VERSION 5.8 ;
BUSBITCHARS "[]" ;
DIVIDERCHAR "/" ;
UNITS
    DATABASE MICRONS 1000 ;
END UNITS

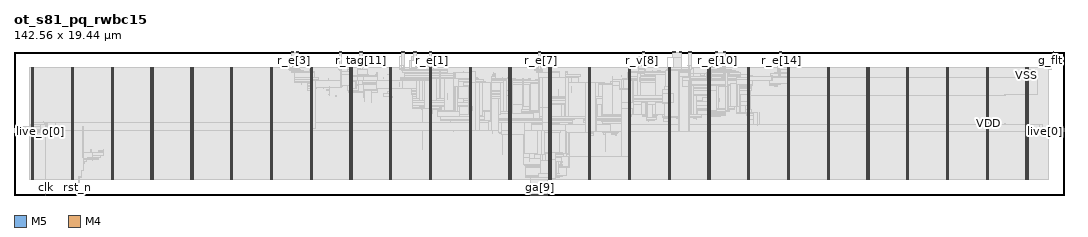
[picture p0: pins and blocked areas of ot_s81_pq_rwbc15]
MACRO ot_s81_pq_rwbc15
  FOREIGN ot_s81_pq_rwbc15 0 0 ;
  CLASS BLOCK ;
  SIZE 142.56 BY 19.44 ;
  PIN clk
    DIRECTION INPUT ;
    USE SIGNAL ;
    PORT
      LAYER M5 ;
        RECT  4.32 0 4.344 0.084 ;
    END
  END clk
  PIN g_flt
    DIRECTION INPUT ;
    USE SIGNAL ;
    PORT
      LAYER M5 ;
        RECT  141.12 19.356 141.144 19.44 ;
    END
  END g_flt
  PIN ga[0]
    DIRECTION OUTPUT ;
    USE SIGNAL ;
    PORT
      LAYER M5 ;
        RECT  70.128 0 70.152 0.084 ;
    END
  END ga[0]
  PIN ga[10]
    DIRECTION OUTPUT ;
    USE SIGNAL ;
    PORT
      LAYER M5 ;
        RECT  71.568 0 71.592 0.084 ;
    END
  END ga[10]
  PIN ga[11]
    DIRECTION OUTPUT ;
    USE SIGNAL ;
    PORT
      LAYER M5 ;
        RECT  71.712 0 71.736 0.084 ;
    END
  END ga[11]
  PIN ga[12]
    DIRECTION OUTPUT ;
    USE SIGNAL ;
    PORT
      LAYER M5 ;
        RECT  71.856 0 71.88 0.084 ;
    END
  END ga[12]
  PIN ga[13]
    DIRECTION OUTPUT ;
    USE SIGNAL ;
    PORT
      LAYER M5 ;
        RECT  72 0 72.024 0.084 ;
    END
  END ga[13]
  PIN ga[14]
    DIRECTION OUTPUT ;
    USE SIGNAL ;
    PORT
      LAYER M5 ;
        RECT  72.144 0 72.168 0.084 ;
    END
  END ga[14]
  PIN ga[15]
    DIRECTION OUTPUT ;
    USE SIGNAL ;
    PORT
      LAYER M5 ;
        RECT  72.288 0 72.312 0.084 ;
    END
  END ga[15]
  PIN ga[1]
    DIRECTION OUTPUT ;
    USE SIGNAL ;
    PORT
      LAYER M5 ;
        RECT  70.272 0 70.296 0.084 ;
    END
  END ga[1]
  PIN ga[2]
    DIRECTION OUTPUT ;
    USE SIGNAL ;
    PORT
      LAYER M5 ;
        RECT  70.416 0 70.44 0.084 ;
    END
  END ga[2]
  PIN ga[3]
    DIRECTION OUTPUT ;
    USE SIGNAL ;
    PORT
      LAYER M5 ;
        RECT  70.56 0 70.584 0.084 ;
    END
  END ga[3]
  PIN ga[4]
    DIRECTION OUTPUT ;
    USE SIGNAL ;
    PORT
      LAYER M5 ;
        RECT  70.704 0 70.728 0.084 ;
    END
  END ga[4]
  PIN ga[5]
    DIRECTION OUTPUT ;
    USE SIGNAL ;
    PORT
      LAYER M5 ;
        RECT  70.848 0 70.872 0.084 ;
    END
  END ga[5]
  PIN ga[6]
    DIRECTION OUTPUT ;
    USE SIGNAL ;
    PORT
      LAYER M5 ;
        RECT  70.992 0 71.016 0.084 ;
    END
  END ga[6]
  PIN ga[7]
    DIRECTION OUTPUT ;
    USE SIGNAL ;
    PORT
      LAYER M5 ;
        RECT  71.136 0 71.16 0.084 ;
    END
  END ga[7]
  PIN ga[8]
    DIRECTION OUTPUT ;
    USE SIGNAL ;
    PORT
      LAYER M5 ;
        RECT  71.28 0 71.304 0.084 ;
    END
  END ga[8]
  PIN ga[9]
    DIRECTION OUTPUT ;
    USE SIGNAL ;
    PORT
      LAYER M5 ;
        RECT  71.424 0 71.448 0.084 ;
    END
  END ga[9]
  PIN live[0]
    DIRECTION INPUT ;
    USE SIGNAL ;
    PORT
      LAYER M4 ;
        RECT  142.476 8.64 142.56 8.664 ;
    END
  END live[0]
  PIN live[1]
    DIRECTION INPUT ;
    USE SIGNAL ;
    PORT
      LAYER M4 ;
        RECT  142.476 8.784 142.56 8.808 ;
    END
  END live[1]
  PIN live[2]
    DIRECTION INPUT ;
    USE SIGNAL ;
    PORT
      LAYER M4 ;
        RECT  142.476 8.928 142.56 8.952 ;
    END
  END live[2]
  PIN live[3]
    DIRECTION INPUT ;
    USE SIGNAL ;
    PORT
      LAYER M4 ;
        RECT  142.476 9.072 142.56 9.096 ;
    END
  END live[3]
  PIN live_o[0]
    DIRECTION OUTPUT ;
    USE SIGNAL ;
    PORT
      LAYER M4 ;
        RECT  0 8.64 0.084 8.664 ;
    END
  END live_o[0]
  PIN live_o[1]
    DIRECTION OUTPUT ;
    USE SIGNAL ;
    PORT
      LAYER M4 ;
        RECT  0 8.784 0.084 8.808 ;
    END
  END live_o[1]
  PIN live_o[2]
    DIRECTION OUTPUT ;
    USE SIGNAL ;
    PORT
      LAYER M4 ;
        RECT  0 8.928 0.084 8.952 ;
    END
  END live_o[2]
  PIN live_o[3]
    DIRECTION OUTPUT ;
    USE SIGNAL ;
    PORT
      LAYER M4 ;
        RECT  0 9.072 0.084 9.096 ;
    END
  END live_o[3]
  PIN q2f
    DIRECTION OUTPUT ;
    USE SIGNAL ;
    PORT
      LAYER M5 ;
        RECT  72.432 0 72.456 0.084 ;
    END
  END q2f
  PIN r_e[0]
    DIRECTION INPUT ;
    USE SIGNAL ;
    PORT
      LAYER M5 ;
        RECT  38.592 19.356 38.616 19.44 ;
    END
  END r_e[0]
  PIN r_e[10]
    DIRECTION INPUT ;
    USE SIGNAL ;
    PORT
      LAYER M5 ;
        RECT  95.472 19.356 95.496 19.44 ;
    END
  END r_e[10]
  PIN r_e[11]
    DIRECTION INPUT ;
    USE SIGNAL ;
    PORT
      LAYER M5 ;
        RECT  90.576 19.356 90.6 19.44 ;
    END
  END r_e[11]
  PIN r_e[12]
    DIRECTION INPUT ;
    USE SIGNAL ;
    PORT
      LAYER M5 ;
        RECT  89.76 19.356 89.784 19.44 ;
    END
  END r_e[12]
  PIN r_e[13]
    DIRECTION INPUT ;
    USE SIGNAL ;
    PORT
      LAYER M5 ;
        RECT  96.576 19.356 96.6 19.44 ;
    END
  END r_e[13]
  PIN r_e[14]
    DIRECTION INPUT ;
    USE SIGNAL ;
    PORT
      LAYER M5 ;
        RECT  104.16 19.356 104.184 19.44 ;
    END
  END r_e[14]
  PIN r_e[1]
    DIRECTION INPUT ;
    USE SIGNAL ;
    PORT
      LAYER M5 ;
        RECT  56.688 19.356 56.712 19.44 ;
    END
  END r_e[1]
  PIN r_e[2]
    DIRECTION INPUT ;
    USE SIGNAL ;
    PORT
      LAYER M5 ;
        RECT  52.944 19.356 52.968 19.44 ;
    END
  END r_e[2]
  PIN r_e[3]
    DIRECTION INPUT ;
    USE SIGNAL ;
    PORT
      LAYER M5 ;
        RECT  37.968 19.356 37.992 19.44 ;
    END
  END r_e[3]
  PIN r_e[4]
    DIRECTION INPUT ;
    USE SIGNAL ;
    PORT
      LAYER M5 ;
        RECT  44.448 19.356 44.472 19.44 ;
    END
  END r_e[4]
  PIN r_e[5]
    DIRECTION INPUT ;
    USE SIGNAL ;
    PORT
      LAYER M5 ;
        RECT  47.232 19.356 47.256 19.44 ;
    END
  END r_e[5]
  PIN r_e[6]
    DIRECTION INPUT ;
    USE SIGNAL ;
    PORT
      LAYER M5 ;
        RECT  54.576 19.356 54.6 19.44 ;
    END
  END r_e[6]
  PIN r_e[7]
    DIRECTION INPUT ;
    USE SIGNAL ;
    PORT
      LAYER M5 ;
        RECT  71.472 19.356 71.496 19.44 ;
    END
  END r_e[7]
  PIN r_e[8]
    DIRECTION INPUT ;
    USE SIGNAL ;
    PORT
      LAYER M5 ;
        RECT  85.584 19.356 85.608 19.44 ;
    END
  END r_e[8]
  PIN r_e[9]
    DIRECTION INPUT ;
    USE SIGNAL ;
    PORT
      LAYER M5 ;
        RECT  91.92 19.356 91.944 19.44 ;
    END
  END r_e[9]
  PIN r_tag[0]
    DIRECTION INPUT ;
    USE SIGNAL ;
    PORT
      LAYER M5 ;
        RECT  38.4 19.356 38.424 19.44 ;
    END
  END r_tag[0]
  PIN r_tag[10]
    DIRECTION INPUT ;
    USE SIGNAL ;
    PORT
      LAYER M5 ;
        RECT  47.04 19.356 47.064 19.44 ;
    END
  END r_tag[10]
  PIN r_tag[11]
    DIRECTION INPUT ;
    USE SIGNAL ;
    PORT
      LAYER M5 ;
        RECT  47.136 19.356 47.16 19.44 ;
    END
  END r_tag[11]
  PIN r_tag[12]
    DIRECTION INPUT ;
    USE SIGNAL ;
    PORT
      LAYER M5 ;
        RECT  54.384 19.356 54.408 19.44 ;
    END
  END r_tag[12]
  PIN r_tag[13]
    DIRECTION INPUT ;
    USE SIGNAL ;
    PORT
      LAYER M5 ;
        RECT  54.48 19.356 54.504 19.44 ;
    END
  END r_tag[13]
  PIN r_tag[14]
    DIRECTION INPUT ;
    USE SIGNAL ;
    PORT
      LAYER M5 ;
        RECT  71.28 19.356 71.304 19.44 ;
    END
  END r_tag[14]
  PIN r_tag[15]
    DIRECTION INPUT ;
    USE SIGNAL ;
    PORT
      LAYER M5 ;
        RECT  71.376 19.356 71.4 19.44 ;
    END
  END r_tag[15]
  PIN r_tag[16]
    DIRECTION INPUT ;
    USE SIGNAL ;
    PORT
      LAYER M5 ;
        RECT  85.392 19.356 85.416 19.44 ;
    END
  END r_tag[16]
  PIN r_tag[17]
    DIRECTION INPUT ;
    USE SIGNAL ;
    PORT
      LAYER M5 ;
        RECT  85.488 19.356 85.512 19.44 ;
    END
  END r_tag[17]
  PIN r_tag[18]
    DIRECTION INPUT ;
    USE SIGNAL ;
    PORT
      LAYER M5 ;
        RECT  91.728 19.356 91.752 19.44 ;
    END
  END r_tag[18]
  PIN r_tag[19]
    DIRECTION INPUT ;
    USE SIGNAL ;
    PORT
      LAYER M5 ;
        RECT  91.824 19.356 91.848 19.44 ;
    END
  END r_tag[19]
  PIN r_tag[1]
    DIRECTION INPUT ;
    USE SIGNAL ;
    PORT
      LAYER M5 ;
        RECT  38.496 19.356 38.52 19.44 ;
    END
  END r_tag[1]
  PIN r_tag[20]
    DIRECTION INPUT ;
    USE SIGNAL ;
    PORT
      LAYER M5 ;
        RECT  95.28 19.356 95.304 19.44 ;
    END
  END r_tag[20]
  PIN r_tag[21]
    DIRECTION INPUT ;
    USE SIGNAL ;
    PORT
      LAYER M5 ;
        RECT  95.376 19.356 95.4 19.44 ;
    END
  END r_tag[21]
  PIN r_tag[22]
    DIRECTION INPUT ;
    USE SIGNAL ;
    PORT
      LAYER M5 ;
        RECT  90.384 19.356 90.408 19.44 ;
    END
  END r_tag[22]
  PIN r_tag[23]
    DIRECTION INPUT ;
    USE SIGNAL ;
    PORT
      LAYER M5 ;
        RECT  90.48 19.356 90.504 19.44 ;
    END
  END r_tag[23]
  PIN r_tag[24]
    DIRECTION INPUT ;
    USE SIGNAL ;
    PORT
      LAYER M5 ;
        RECT  89.568 19.356 89.592 19.44 ;
    END
  END r_tag[24]
  PIN r_tag[25]
    DIRECTION INPUT ;
    USE SIGNAL ;
    PORT
      LAYER M5 ;
        RECT  89.664 19.356 89.688 19.44 ;
    END
  END r_tag[25]
  PIN r_tag[26]
    DIRECTION INPUT ;
    USE SIGNAL ;
    PORT
      LAYER M5 ;
        RECT  96.384 19.356 96.408 19.44 ;
    END
  END r_tag[26]
  PIN r_tag[27]
    DIRECTION INPUT ;
    USE SIGNAL ;
    PORT
      LAYER M5 ;
        RECT  96.48 19.356 96.504 19.44 ;
    END
  END r_tag[27]
  PIN r_tag[28]
    DIRECTION INPUT ;
    USE SIGNAL ;
    PORT
      LAYER M5 ;
        RECT  103.968 19.356 103.992 19.44 ;
    END
  END r_tag[28]
  PIN r_tag[29]
    DIRECTION INPUT ;
    USE SIGNAL ;
    PORT
      LAYER M5 ;
        RECT  104.064 19.356 104.088 19.44 ;
    END
  END r_tag[29]
  PIN r_tag[2]
    DIRECTION INPUT ;
    USE SIGNAL ;
    PORT
      LAYER M5 ;
        RECT  56.496 19.356 56.52 19.44 ;
    END
  END r_tag[2]
  PIN r_tag[3]
    DIRECTION INPUT ;
    USE SIGNAL ;
    PORT
      LAYER M5 ;
        RECT  56.592 19.356 56.616 19.44 ;
    END
  END r_tag[3]
  PIN r_tag[4]
    DIRECTION INPUT ;
    USE SIGNAL ;
    PORT
      LAYER M5 ;
        RECT  52.752 19.356 52.776 19.44 ;
    END
  END r_tag[4]
  PIN r_tag[5]
    DIRECTION INPUT ;
    USE SIGNAL ;
    PORT
      LAYER M5 ;
        RECT  52.848 19.356 52.872 19.44 ;
    END
  END r_tag[5]
  PIN r_tag[6]
    DIRECTION INPUT ;
    USE SIGNAL ;
    PORT
      LAYER M5 ;
        RECT  37.776 19.356 37.8 19.44 ;
    END
  END r_tag[6]
  PIN r_tag[7]
    DIRECTION INPUT ;
    USE SIGNAL ;
    PORT
      LAYER M5 ;
        RECT  37.872 19.356 37.896 19.44 ;
    END
  END r_tag[7]
  PIN r_tag[8]
    DIRECTION INPUT ;
    USE SIGNAL ;
    PORT
      LAYER M5 ;
        RECT  44.256 19.356 44.28 19.44 ;
    END
  END r_tag[8]
  PIN r_tag[9]
    DIRECTION INPUT ;
    USE SIGNAL ;
    PORT
      LAYER M5 ;
        RECT  44.352 19.356 44.376 19.44 ;
    END
  END r_tag[9]
  PIN r_v[0]
    DIRECTION INPUT ;
    USE SIGNAL ;
    PORT
      LAYER M5 ;
        RECT  38.304 19.356 38.328 19.44 ;
    END
  END r_v[0]
  PIN r_v[10]
    DIRECTION INPUT ;
    USE SIGNAL ;
    PORT
      LAYER M5 ;
        RECT  95.184 19.356 95.208 19.44 ;
    END
  END r_v[10]
  PIN r_v[11]
    DIRECTION INPUT ;
    USE SIGNAL ;
    PORT
      LAYER M5 ;
        RECT  90.288 19.356 90.312 19.44 ;
    END
  END r_v[11]
  PIN r_v[12]
    DIRECTION INPUT ;
    USE SIGNAL ;
    PORT
      LAYER M5 ;
        RECT  89.472 19.356 89.496 19.44 ;
    END
  END r_v[12]
  PIN r_v[13]
    DIRECTION INPUT ;
    USE SIGNAL ;
    PORT
      LAYER M5 ;
        RECT  96.288 19.356 96.312 19.44 ;
    END
  END r_v[13]
  PIN r_v[14]
    DIRECTION INPUT ;
    USE SIGNAL ;
    PORT
      LAYER M5 ;
        RECT  103.872 19.356 103.896 19.44 ;
    END
  END r_v[14]
  PIN r_v[1]
    DIRECTION INPUT ;
    USE SIGNAL ;
    PORT
      LAYER M5 ;
        RECT  56.4 19.356 56.424 19.44 ;
    END
  END r_v[1]
  PIN r_v[2]
    DIRECTION INPUT ;
    USE SIGNAL ;
    PORT
      LAYER M5 ;
        RECT  52.656 19.356 52.68 19.44 ;
    END
  END r_v[2]
  PIN r_v[3]
    DIRECTION INPUT ;
    USE SIGNAL ;
    PORT
      LAYER M5 ;
        RECT  37.68 19.356 37.704 19.44 ;
    END
  END r_v[3]
  PIN r_v[4]
    DIRECTION INPUT ;
    USE SIGNAL ;
    PORT
      LAYER M5 ;
        RECT  44.16 19.356 44.184 19.44 ;
    END
  END r_v[4]
  PIN r_v[5]
    DIRECTION INPUT ;
    USE SIGNAL ;
    PORT
      LAYER M5 ;
        RECT  46.944 19.356 46.968 19.44 ;
    END
  END r_v[5]
  PIN r_v[6]
    DIRECTION INPUT ;
    USE SIGNAL ;
    PORT
      LAYER M5 ;
        RECT  54.288 19.356 54.312 19.44 ;
    END
  END r_v[6]
  PIN r_v[7]
    DIRECTION INPUT ;
    USE SIGNAL ;
    PORT
      LAYER M5 ;
        RECT  71.184 19.356 71.208 19.44 ;
    END
  END r_v[7]
  PIN r_v[8]
    DIRECTION INPUT ;
    USE SIGNAL ;
    PORT
      LAYER M5 ;
        RECT  85.296 19.356 85.32 19.44 ;
    END
  END r_v[8]
  PIN r_v[9]
    DIRECTION INPUT ;
    USE SIGNAL ;
    PORT
      LAYER M5 ;
        RECT  91.632 19.356 91.656 19.44 ;
    END
  END r_v[9]
  PIN rst_n
    DIRECTION INPUT ;
    USE SIGNAL ;
    PORT
      LAYER M5 ;
        RECT  8.64 0 8.664 0.084 ;
    END
  END rst_n
  PIN VDD
    DIRECTION INOUT ;
    USE POWER ;
    PORT
      LAYER M5 ;
        RECT  137.592 2.151 137.712 17.289 ;
        RECT  132.192 2.151 132.312 17.289 ;
        RECT  126.792 2.151 126.912 17.289 ;
        RECT  121.392 2.151 121.512 17.289 ;
        RECT  115.992 2.151 116.112 17.289 ;
        RECT  110.592 2.151 110.712 17.289 ;
        RECT  105.192 2.151 105.312 17.289 ;
        RECT  99.792 2.151 99.912 17.289 ;
        RECT  94.392 2.151 94.512 17.289 ;
        RECT  88.992 2.151 89.112 17.289 ;
        RECT  83.592 2.151 83.712 17.289 ;
        RECT  78.192 2.151 78.312 17.289 ;
        RECT  72.792 2.151 72.912 17.289 ;
        RECT  67.392 2.151 67.512 17.289 ;
        RECT  61.992 2.151 62.112 17.289 ;
        RECT  56.592 2.151 56.712 17.289 ;
        RECT  51.192 2.151 51.312 17.289 ;
        RECT  45.792 2.151 45.912 17.289 ;
        RECT  40.392 2.151 40.512 17.289 ;
        RECT  34.992 2.151 35.112 17.289 ;
        RECT  29.592 2.151 29.712 17.289 ;
        RECT  24.192 2.151 24.312 17.289 ;
        RECT  18.792 2.151 18.912 17.289 ;
        RECT  13.392 2.151 13.512 17.289 ;
        RECT  7.992 2.151 8.112 17.289 ;
        RECT  2.592 2.151 2.712 17.289 ;
    END
  END VDD
  PIN VSS
    DIRECTION INOUT ;
    USE GROUND ;
    PORT
      LAYER M5 ;
        RECT  137.4 2.137 137.52 17.303 ;
        RECT  132 2.137 132.12 17.303 ;
        RECT  126.6 2.137 126.72 17.303 ;
        RECT  121.2 2.137 121.32 17.303 ;
        RECT  115.8 2.137 115.92 17.303 ;
        RECT  110.4 2.137 110.52 17.303 ;
        RECT  105 2.137 105.12 17.303 ;
        RECT  99.6 2.137 99.72 17.303 ;
        RECT  94.2 2.137 94.32 17.303 ;
        RECT  88.8 2.137 88.92 17.303 ;
        RECT  83.4 2.137 83.52 17.303 ;
        RECT  78 2.137 78.12 17.303 ;
        RECT  72.6 2.137 72.72 17.303 ;
        RECT  67.2 2.137 67.32 17.303 ;
        RECT  61.8 2.137 61.92 17.303 ;
        RECT  56.4 2.137 56.52 17.303 ;
        RECT  51 2.137 51.12 17.303 ;
        RECT  45.6 2.137 45.72 17.303 ;
        RECT  40.2 2.137 40.32 17.303 ;
        RECT  34.8 2.137 34.92 17.303 ;
        RECT  29.4 2.137 29.52 17.303 ;
        RECT  24 2.137 24.12 17.303 ;
        RECT  18.6 2.137 18.72 17.303 ;
        RECT  13.2 2.137 13.32 17.303 ;
        RECT  7.8 2.137 7.92 17.303 ;
        RECT  2.4 2.137 2.52 17.303 ;
    END
  END VSS
  OBS
    LAYER RVTN ;
     RECT  2.16 2.16 140.4 2.295 ;
     RECT  2.16 2.565 140.4 2.835 ;
     RECT  2.16 3.105 140.4 3.375 ;
     RECT  2.16 3.645 140.4 3.915 ;
     RECT  2.16 4.185 140.4 4.455 ;
     RECT  2.16 4.725 140.4 4.995 ;
     RECT  2.16 5.265 140.4 5.535 ;
     RECT  2.16 5.805 140.4 6.075 ;
     RECT  2.16 6.345 140.4 6.615 ;
     RECT  2.16 6.885 140.4 7.155 ;
     RECT  2.16 7.425 140.4 7.695 ;
     RECT  2.16 7.965 140.4 8.235 ;
     RECT  2.16 8.505 140.4 8.775 ;
     RECT  2.16 9.045 140.4 9.315 ;
     RECT  2.16 9.585 140.4 9.855 ;
     RECT  2.16 10.125 140.4 10.395 ;
     RECT  2.16 10.665 140.4 10.935 ;
     RECT  2.16 11.205 140.4 11.475 ;
     RECT  2.16 11.745 140.4 12.015 ;
     RECT  2.16 12.285 140.4 12.555 ;
     RECT  2.16 12.825 140.4 13.095 ;
     RECT  2.16 13.365 140.4 13.635 ;
     RECT  2.16 13.905 140.4 14.175 ;
     RECT  2.16 14.445 140.4 14.715 ;
     RECT  2.16 14.985 140.4 15.255 ;
     RECT  2.16 15.525 140.4 15.795 ;
     RECT  2.16 16.065 140.4 16.335 ;
     RECT  2.16 16.605 140.4 16.875 ;
     RECT  2.16 17.145 140.4 17.28 ;
    LAYER RVTP ;
     RECT  2.16 2.295 140.4 2.565 ;
     RECT  2.16 2.835 140.4 3.105 ;
     RECT  2.16 3.375 140.4 3.645 ;
     RECT  2.16 3.915 140.4 4.185 ;
     RECT  2.16 4.455 140.4 4.725 ;
     RECT  2.16 4.995 140.4 5.265 ;
     RECT  2.16 5.535 140.4 5.805 ;
     RECT  2.16 6.075 140.4 6.345 ;
     RECT  2.16 6.615 140.4 6.885 ;
     RECT  2.16 7.155 140.4 7.425 ;
     RECT  2.16 7.695 140.4 7.965 ;
     RECT  2.16 8.235 140.4 8.505 ;
     RECT  2.16 8.775 140.4 9.045 ;
     RECT  2.16 9.315 140.4 9.585 ;
     RECT  2.16 9.855 140.4 10.125 ;
     RECT  2.16 10.395 140.4 10.665 ;
     RECT  2.16 10.935 140.4 11.205 ;
     RECT  2.16 11.475 140.4 11.745 ;
     RECT  2.16 12.015 140.4 12.285 ;
     RECT  2.16 12.555 140.4 12.825 ;
     RECT  2.16 13.095 140.4 13.365 ;
     RECT  2.16 13.635 140.4 13.905 ;
     RECT  2.16 14.175 140.4 14.445 ;
     RECT  2.16 14.715 140.4 14.985 ;
     RECT  2.16 15.255 140.4 15.525 ;
     RECT  2.16 15.795 140.4 16.065 ;
     RECT  2.16 16.335 140.4 16.605 ;
     RECT  2.16 16.875 140.4 17.145 ;
    LAYER M1 ;
     RECT  2.16 2.151 140.4 17.289 ;
    LAYER M2 ;
     RECT  0.103 8.514 0.535 8.532 ;
     RECT  0.535 8.316 2.16 8.532 ;
     RECT  2.16 2.151 71.671 17.289 ;
     RECT  71.671 2.106 72.995 17.289 ;
     RECT  72.995 2.151 140.4 17.289 ;
     RECT  140.4 17.082 140.819 17.1 ;
    LAYER M3 ;
     RECT  70.956 0.091 71.658 0.523 ;
     RECT  70.704 0.523 71.658 1.099 ;
     RECT  70.272 1.099 71.658 1.723 ;
     RECT  70.272 1.723 72.198 2.143 ;
     RECT  72.972 2.101 72.99 2.143 ;
     RECT  70.272 2.143 72.99 2.263 ;
     RECT  70.2 2.263 72.99 2.299 ;
     RECT  8.82 1.723 8.838 2.335 ;
     RECT  70.128 2.299 73.458 2.335 ;
     RECT  8.82 2.335 9.018 2.371 ;
     RECT  69.48 2.335 73.458 2.371 ;
     RECT  2.415 2.143 2.505 2.413 ;
     RECT  7.815 2.143 7.905 2.413 ;
     RECT  13.215 2.143 13.305 2.413 ;
     RECT  18.615 2.143 18.705 2.413 ;
     RECT  24.015 2.143 24.105 2.413 ;
     RECT  29.415 2.143 29.505 2.413 ;
     RECT  34.815 2.143 34.905 2.413 ;
     RECT  40.215 2.143 40.305 2.413 ;
     RECT  45.615 2.143 45.705 2.413 ;
     RECT  51.015 2.143 51.105 2.413 ;
     RECT  56.415 2.143 56.505 2.413 ;
     RECT  61.815 2.143 61.905 2.413 ;
     RECT  67.215 2.143 67.305 2.413 ;
     RECT  78.015 2.143 78.105 2.413 ;
     RECT  83.415 2.143 83.505 2.413 ;
     RECT  88.815 2.143 88.905 2.413 ;
     RECT  94.215 2.143 94.305 2.413 ;
     RECT  99.615 2.143 99.705 2.413 ;
     RECT  105.015 2.143 105.105 2.413 ;
     RECT  110.415 2.143 110.505 2.413 ;
     RECT  115.815 2.143 115.905 2.413 ;
     RECT  121.215 2.143 121.305 2.413 ;
     RECT  126.615 2.143 126.705 2.413 ;
     RECT  132.015 2.143 132.105 2.413 ;
     RECT  137.415 2.143 137.505 2.413 ;
     RECT  69.48 2.371 73.998 2.497 ;
     RECT  8.82 2.371 9.126 2.525 ;
     RECT  69.48 2.497 74.466 2.641 ;
     RECT  9.108 2.525 9.126 3.271 ;
     RECT  9.108 3.271 9.45 3.335 ;
     RECT  69.48 2.641 74.97 3.685 ;
     RECT  69.48 3.685 75.402 3.839 ;
     RECT  69.48 3.839 74.502 3.955 ;
     RECT  69.372 3.955 74.502 4.109 ;
     RECT  69.372 4.109 74.394 4.117 ;
     RECT  9.432 3.335 9.45 4.145 ;
     RECT  9.468 4.261 9.594 4.531 ;
     RECT  9.468 4.531 9.81 4.765 ;
     RECT  10.62 4.729 10.638 4.765 ;
     RECT  9.468 4.765 10.746 4.801 ;
     RECT  9.468 4.801 11.43 4.919 ;
     RECT  10.044 4.919 11.43 5.027 ;
     RECT  10.116 5.027 11.43 5.035 ;
     RECT  10.116 5.035 11.574 5.063 ;
     RECT  69.156 4.117 74.394 5.069 ;
     RECT  10.62 5.063 11.574 5.071 ;
     RECT  9.288 5.071 9.306 5.117 ;
     RECT  69.3 5.069 74.394 5.179 ;
     RECT  75.312 3.839 75.402 5.179 ;
     RECT  10.62 5.071 11.79 5.305 ;
     RECT  69.3 5.179 75.402 5.459 ;
     RECT  71.892 5.459 75.402 5.549 ;
     RECT  69.3 5.459 71.046 5.603 ;
     RECT  71.964 5.549 75.402 5.693 ;
     RECT  10.62 5.305 12.186 5.729 ;
     RECT  71.964 5.693 74.394 5.741 ;
     RECT  11.304 5.729 12.186 5.765 ;
     RECT  11.412 5.765 12.186 5.909 ;
     RECT  11.52 5.909 12.186 5.999 ;
     RECT  11.916 5.999 12.186 6.107 ;
     RECT  10.44 5.803 10.458 6.143 ;
     RECT  12.168 6.107 12.186 6.143 ;
     RECT  78.015 2.413 78.297 8.131 ;
     RECT  81.612 8.131 81.738 8.203 ;
     RECT  80.244 5.971 80.262 8.239 ;
     RECT  81.072 8.203 81.738 8.275 ;
     RECT  2.415 2.413 2.697 8.311 ;
     RECT  66.348 5.539 66.366 8.311 ;
     RECT  78.015 8.131 78.678 8.311 ;
     RECT  2.415 8.311 3.15 8.401 ;
     RECT  81.072 8.275 81.846 8.401 ;
     RECT  78.015 8.311 78.714 8.429 ;
     RECT  65.952 8.311 66.366 8.437 ;
     RECT  67.215 2.413 67.497 8.437 ;
     RECT  80.064 8.239 80.262 8.437 ;
     RECT  81.072 8.401 81.882 8.437 ;
     RECT  80.064 8.437 81.882 8.473 ;
     RECT  65.808 8.437 67.497 8.477 ;
     RECT  0.54 8.311 0.558 8.509 ;
     RECT  2.415 8.401 3.222 8.509 ;
     RECT  71.964 5.741 74.106 8.509 ;
     RECT  78.015 8.429 78.678 8.537 ;
     RECT  2.415 8.509 3.258 8.545 ;
     RECT  79.848 8.473 81.99 8.545 ;
     RECT  79.848 8.545 82.062 8.573 ;
     RECT  66.24 8.477 67.497 8.581 ;
     RECT  139.788 8.437 139.806 8.581 ;
     RECT  0.108 8.509 0.558 8.669 ;
     RECT  2.415 8.545 3.654 8.671 ;
     RECT  88.815 2.413 89.097 8.671 ;
     RECT  99.615 2.413 99.897 8.671 ;
     RECT  110.415 2.413 110.697 8.671 ;
     RECT  121.215 2.413 121.497 8.671 ;
     RECT  132.015 2.413 132.297 8.671 ;
     RECT  139.788 8.581 139.986 8.671 ;
     RECT  137.415 2.413 137.697 8.683 ;
     RECT  138.852 8.581 138.87 8.683 ;
     RECT  66.24 8.581 67.518 8.699 ;
     RECT  71.964 8.509 74.214 8.699 ;
     RECT  99.504 8.671 99.897 8.707 ;
     RECT  88.704 8.671 89.097 8.717 ;
     RECT  99.504 8.707 99.99 8.717 ;
     RECT  110.304 8.671 110.697 8.717 ;
     RECT  121.104 8.671 121.497 8.717 ;
     RECT  131.904 8.671 132.297 8.717 ;
     RECT  137.304 8.683 137.697 8.735 ;
     RECT  2.415 8.671 4.41 8.743 ;
     RECT  2.415 8.743 4.626 8.771 ;
     RECT  137.415 8.735 137.697 8.779 ;
     RECT  138.528 8.683 138.87 8.779 ;
     RECT  139.608 8.671 139.986 8.779 ;
     RECT  0.54 8.669 0.558 8.813 ;
     RECT  4.392 8.771 4.626 8.813 ;
     RECT  137.415 8.779 139.986 8.813 ;
     RECT  66.24 8.699 67.497 8.843 ;
     RECT  138.924 8.813 139.986 8.843 ;
     RECT  5.58 8.731 5.598 8.851 ;
     RECT  2.415 8.771 3.654 8.923 ;
     RECT  138.996 8.843 139.986 8.923 ;
     RECT  6.66 8.851 6.678 8.941 ;
     RECT  40.215 2.413 40.497 8.941 ;
     RECT  5.364 8.851 5.598 8.969 ;
     RECT  6.66 8.941 7.074 8.969 ;
     RECT  138.996 8.923 140.058 8.969 ;
     RECT  5.436 8.969 5.598 8.971 ;
     RECT  61.815 2.413 62.097 8.977 ;
     RECT  139.068 8.969 140.058 9.005 ;
     RECT  5.436 8.971 5.886 9.011 ;
     RECT  79.956 8.573 82.062 9.013 ;
     RECT  79.956 9.013 82.134 9.049 ;
     RECT  61.815 8.977 62.766 9.085 ;
     RECT  6.804 8.969 7.074 9.101 ;
     RECT  40.215 8.941 40.878 9.121 ;
     RECT  64.98 8.311 64.998 9.121 ;
     RECT  34.815 2.413 35.097 9.205 ;
     RECT  13.215 2.413 13.497 9.211 ;
     RECT  24.015 2.413 24.297 9.211 ;
     RECT  40.215 9.121 41.058 9.211 ;
     RECT  45.615 2.413 45.897 9.211 ;
     RECT  4.392 8.813 4.554 9.239 ;
     RECT  100.8 9.049 100.818 9.239 ;
     RECT  137.415 8.813 138.078 9.239 ;
     RECT  34.704 9.205 35.097 9.245 ;
     RECT  13.104 9.211 13.497 9.248 ;
     RECT  23.904 9.211 24.297 9.248 ;
     RECT  45.504 9.211 45.897 9.248 ;
     RECT  59.652 8.671 59.67 9.307 ;
     RECT  61.815 9.085 63.198 9.307 ;
     RECT  2.376 8.923 3.654 9.319 ;
     RECT  59.472 9.307 59.67 9.319 ;
     RECT  61.704 9.307 63.198 9.319 ;
     RECT  64.332 9.121 64.998 9.319 ;
     RECT  78.015 8.537 78.297 9.319 ;
     RECT  40.104 9.211 41.058 9.341 ;
     RECT  53.028 9.211 53.046 9.341 ;
     RECT  59.472 9.319 60.246 9.355 ;
     RECT  79.956 9.049 82.206 9.355 ;
     RECT  59.472 9.355 60.354 9.391 ;
     RECT  69.3 5.603 71.01 9.391 ;
     RECT  71.964 8.699 74.106 9.391 ;
     RECT  99.615 8.717 99.99 9.391 ;
     RECT  59.472 9.391 60.93 9.481 ;
     RECT  68.544 9.121 68.562 9.481 ;
     RECT  68.256 9.481 68.562 9.517 ;
     RECT  69.3 9.391 74.106 9.517 ;
     RECT  2.304 9.319 3.654 9.545 ;
     RECT  5.868 9.011 5.886 9.545 ;
     RECT  139.212 9.005 139.626 9.545 ;
     RECT  66.348 8.843 67.497 9.553 ;
     RECT  68.256 9.517 74.106 9.553 ;
     RECT  137.415 9.239 137.97 9.581 ;
     RECT  139.212 9.545 139.23 9.581 ;
     RECT  2.34 9.545 3.654 9.589 ;
     RECT  99.615 9.391 100.35 9.589 ;
     RECT  2.34 9.589 4.302 9.617 ;
     RECT  6.012 9.547 6.03 9.617 ;
     RECT  61.704 9.319 65.466 9.625 ;
     RECT  66.348 9.553 74.106 9.625 ;
     RECT  59.292 9.481 60.93 9.661 ;
     RECT  61.704 9.625 74.106 9.661 ;
     RECT  6.804 9.101 6.822 9.689 ;
     RECT  134.532 8.581 134.55 9.689 ;
     RECT  79.956 9.355 82.566 9.691 ;
     RECT  75.312 5.693 75.402 9.751 ;
     RECT  2.415 9.617 4.302 9.779 ;
     RECT  59.292 9.661 74.106 9.823 ;
     RECT  75.312 9.751 75.762 9.823 ;
     RECT  78.015 9.319 78.678 9.859 ;
     RECT  77.724 9.859 78.678 9.895 ;
     RECT  3.96 9.779 3.978 9.923 ;
     RECT  79.956 9.691 82.674 9.931 ;
     RECT  88.815 8.717 89.097 9.931 ;
     RECT  59.292 9.823 75.762 10.057 ;
     RECT  77.256 9.895 78.678 10.057 ;
     RECT  79.776 9.931 82.674 10.057 ;
     RECT  86.148 9.931 86.166 10.057 ;
     RECT  85.932 10.057 86.166 10.093 ;
     RECT  86.904 10.057 86.922 10.093 ;
     RECT  57.96 10.057 75.762 10.157 ;
     RECT  57.96 10.157 63.882 10.193 ;
     RECT  85.932 10.093 86.922 10.201 ;
     RECT  99.576 9.589 100.35 10.201 ;
     RECT  64.656 10.157 75.762 10.291 ;
     RECT  77.256 10.057 82.674 10.291 ;
     RECT  83.415 2.413 83.697 10.291 ;
     RECT  64.656 10.291 76.086 10.319 ;
     RECT  77.256 10.291 83.697 10.363 ;
     RECT  71.352 10.319 76.086 10.399 ;
     RECT  76.932 10.363 83.697 10.399 ;
     RECT  92.7 10.291 92.718 10.399 ;
     RECT  88.236 9.931 89.097 10.435 ;
     RECT  91.224 10.399 91.242 10.435 ;
     RECT  85.932 10.201 87.246 10.471 ;
     RECT  88.128 10.435 89.097 10.471 ;
     RECT  89.964 10.435 90.27 10.471 ;
     RECT  91.116 10.435 91.242 10.471 ;
     RECT  92.232 10.399 92.718 10.471 ;
     RECT  85.932 10.471 87.282 10.555 ;
     RECT  88.092 10.471 89.097 10.561 ;
     RECT  89.964 10.471 92.718 10.561 ;
     RECT  85.86 10.555 87.282 10.597 ;
     RECT  95.868 10.597 95.886 10.633 ;
     RECT  71.352 10.399 83.697 10.669 ;
     RECT  88.092 10.561 93.33 10.669 ;
     RECT  94.215 2.413 94.497 10.669 ;
     RECT  95.76 10.633 95.886 10.669 ;
     RECT  57.96 10.193 63.846 10.705 ;
     RECT  94.215 10.669 95.886 10.741 ;
     RECT  71.352 10.669 83.898 10.769 ;
     RECT  85.356 10.597 87.282 10.831 ;
     RECT  99.54 10.201 100.35 10.831 ;
     RECT  76.752 10.769 83.898 10.867 ;
     RECT  85.356 10.831 87.318 10.867 ;
     RECT  71.352 10.769 75.726 10.895 ;
     RECT  76.752 10.867 83.97 10.895 ;
     RECT  84.96 10.867 87.318 10.933 ;
     RECT  88.092 10.669 93.366 10.933 ;
     RECT  56.415 2.413 56.697 10.975 ;
     RECT  84.96 10.933 93.366 10.987 ;
     RECT  94.215 10.741 96.534 10.987 ;
     RECT  56.376 10.975 56.697 11.011 ;
     RECT  99.468 10.831 100.35 11.011 ;
     RECT  64.656 10.319 70.542 11.129 ;
     RECT  84.96 10.987 96.534 11.129 ;
     RECT  101.16 9.391 101.178 11.165 ;
     RECT  76.932 10.895 83.97 11.173 ;
     RECT  99.396 11.011 100.35 11.173 ;
     RECT  68.94 11.129 70.542 11.179 ;
     RECT  71.352 10.895 75.69 11.179 ;
     RECT  99.36 11.173 100.35 11.201 ;
     RECT  87.804 11.129 96.534 11.245 ;
     RECT  87.804 11.245 96.57 11.281 ;
     RECT  57.492 10.705 63.846 11.371 ;
     RECT  64.656 11.129 67.734 11.371 ;
     RECT  76.932 11.173 84.15 11.371 ;
     RECT  84.96 11.129 86.814 11.371 ;
     RECT  87.804 11.281 96.966 11.371 ;
     RECT  68.94 11.179 75.69 11.399 ;
     RECT  57.492 11.371 67.734 11.435 ;
     RECT  57.492 11.435 66.006 11.507 ;
     RECT  87.804 11.371 97.146 11.551 ;
     RECT  68.94 11.399 74.106 11.579 ;
     RECT  55.44 6.151 55.458 11.641 ;
     RECT  56.376 11.011 56.754 11.641 ;
     RECT  57.492 11.507 65.97 11.641 ;
     RECT  99.36 11.201 100.098 11.669 ;
     RECT  87.804 11.551 97.758 11.741 ;
     RECT  56.376 11.641 65.97 11.749 ;
     RECT  55.332 11.641 55.458 11.785 ;
     RECT  75.168 11.399 75.69 11.785 ;
     RECT  55.152 11.785 55.458 11.821 ;
     RECT  75.168 11.785 76.122 11.911 ;
     RECT  76.932 11.371 86.814 11.911 ;
     RECT  75.168 11.911 86.814 11.939 ;
     RECT  79.92 11.939 86.814 11.947 ;
     RECT  87.804 11.741 91.314 11.947 ;
     RECT  69.048 11.579 74.106 11.975 ;
     RECT  55.044 11.821 55.458 11.983 ;
     RECT  56.232 11.749 65.97 11.983 ;
     RECT  55.044 11.983 65.97 12.083 ;
     RECT  54.108 11.803 54.126 12.091 ;
     RECT  55.044 12.083 62.097 12.091 ;
     RECT  98.532 11.995 98.55 12.091 ;
     RECT  99.36 11.669 99.954 12.091 ;
     RECT  92.052 11.741 97.758 12.181 ;
     RECT  98.532 12.091 99.954 12.181 ;
     RECT  75.168 11.939 79.11 12.289 ;
     RECT  62.892 12.083 65.97 12.361 ;
     RECT  69.048 11.975 70.542 12.361 ;
     RECT  71.676 11.975 74.106 12.361 ;
     RECT  74.844 12.289 79.11 12.361 ;
     RECT  62.892 12.361 66.15 12.487 ;
     RECT  54.108 12.091 62.097 12.551 ;
     RECT  62.892 12.487 66.222 12.559 ;
     RECT  66.96 11.435 67.734 12.559 ;
     RECT  79.92 11.947 91.314 12.631 ;
     RECT  92.052 12.181 99.954 12.631 ;
     RECT  62.892 12.559 67.734 12.757 ;
     RECT  54.108 12.551 60.21 12.829 ;
     RECT  60.984 12.551 62.097 12.829 ;
     RECT  62.892 12.757 67.914 12.829 ;
     RECT  71.676 12.361 79.11 12.893 ;
     RECT  79.92 12.631 99.954 12.901 ;
     RECT  60.984 12.829 67.914 13.055 ;
     RECT  71.676 12.893 77.022 13.063 ;
     RECT  71.568 13.063 77.022 13.091 ;
     RECT  71.568 13.091 76.842 13.099 ;
     RECT  77.904 12.893 79.11 13.135 ;
     RECT  79.92 12.901 99.99 13.135 ;
     RECT  71.388 13.099 76.842 13.199 ;
     RECT  51.015 2.413 51.297 13.261 ;
     RECT  47.592 12.631 47.61 13.297 ;
     RECT  51.015 13.261 51.354 13.369 ;
     RECT  54.072 12.829 60.21 13.369 ;
     RECT  68.976 12.361 70.542 13.369 ;
     RECT  71.388 13.199 76.77 13.369 ;
     RECT  50.724 13.369 51.354 13.397 ;
     RECT  50.724 13.397 51.297 13.405 ;
     RECT  54.072 13.369 60.246 13.441 ;
     RECT  60.984 13.055 67.698 13.441 ;
     RECT  110.415 8.717 110.697 13.525 ;
     RECT  121.215 8.717 121.497 13.531 ;
     RECT  132.015 8.717 132.297 13.531 ;
     RECT  43.704 13.369 43.722 13.559 ;
     RECT  68.868 13.369 76.77 13.559 ;
     RECT  110.304 13.525 110.697 13.565 ;
     RECT  77.904 13.135 99.99 13.568 ;
     RECT  121.104 13.531 121.497 13.568 ;
     RECT  131.904 13.531 132.297 13.568 ;
     RECT  54.072 13.441 67.698 13.639 ;
     RECT  77.94 13.568 99.99 13.639 ;
     RECT  134.532 13.531 134.55 13.661 ;
     RECT  42.768 13.531 42.786 13.711 ;
     RECT  68.868 13.559 76.626 13.801 ;
     RECT  50.184 13.405 51.297 13.829 ;
     RECT  53.964 13.639 67.698 13.837 ;
     RECT  45.615 9.248 45.897 13.945 ;
     RECT  45.36 13.945 46.53 13.981 ;
     RECT  47.412 13.297 47.61 13.981 ;
     RECT  48.564 12.595 48.582 13.981 ;
     RECT  45.36 13.981 47.61 14.099 ;
     RECT  50.688 13.829 51.297 14.099 ;
     RECT  53.964 13.837 67.806 14.107 ;
     RECT  68.616 13.801 76.626 14.107 ;
     RECT  53.964 14.107 76.626 14.135 ;
     RECT  40.215 9.341 40.497 14.143 ;
     RECT  45.36 14.099 46.71 14.179 ;
     RECT  42.768 13.711 42.894 14.215 ;
     RECT  47.484 14.099 47.61 14.251 ;
     RECT  48.564 13.981 49.41 14.251 ;
     RECT  77.94 13.639 100.026 14.251 ;
     RECT  42.444 14.215 42.894 14.369 ;
     RECT  47.484 14.251 49.41 14.369 ;
     RECT  77.94 14.251 100.098 14.405 ;
     RECT  53.964 14.135 63.234 14.443 ;
     RECT  79.236 14.405 100.098 14.485 ;
     RECT  39.852 14.143 40.497 14.521 ;
     RECT  41.976 14.485 41.994 14.611 ;
     RECT  77.94 14.405 78.354 14.611 ;
     RECT  53.424 14.443 63.234 14.635 ;
     RECT  53.316 14.635 63.234 14.639 ;
     RECT  79.236 14.485 100.17 14.639 ;
     RECT  64.152 14.135 76.626 14.647 ;
     RECT  77.436 14.611 78.354 14.647 ;
     RECT  79.344 14.639 100.17 14.675 ;
     RECT  39.852 14.521 41.022 14.791 ;
     RECT  41.796 14.611 41.994 14.791 ;
     RECT  44.352 14.635 44.37 14.791 ;
     RECT  52.344 14.731 52.362 14.791 ;
     RECT  53.316 14.639 60.318 14.791 ;
     RECT  103.608 14.755 103.626 14.791 ;
     RECT  43.02 14.791 44.55 14.875 ;
     RECT  45.324 14.179 46.71 14.875 ;
     RECT  61.092 14.639 63.234 14.881 ;
     RECT  64.152 14.647 78.354 14.881 ;
     RECT  82.656 14.675 100.17 14.881 ;
     RECT  103.32 14.791 103.626 14.881 ;
     RECT  39.852 14.791 41.994 14.909 ;
     RECT  43.02 14.875 46.71 14.909 ;
     RECT  61.092 14.881 78.354 14.909 ;
     RECT  50.148 14.881 50.166 14.917 ;
     RECT  51.015 14.099 51.297 14.917 ;
     RECT  44.208 14.909 44.226 14.945 ;
     RECT  45.108 14.909 46.71 14.971 ;
     RECT  47.484 14.369 49.266 14.971 ;
     RECT  43.02 14.909 43.29 14.981 ;
     RECT  82.656 14.881 100.206 15.025 ;
     RECT  102.636 14.881 103.626 15.025 ;
     RECT  50.148 14.917 51.297 15.061 ;
     RECT  52.344 14.791 60.318 15.061 ;
     RECT  102.6 15.025 103.626 15.061 ;
     RECT  50.148 15.061 60.318 15.089 ;
     RECT  77.436 14.909 78.297 15.089 ;
     RECT  79.344 14.675 81.918 15.089 ;
     RECT  45.108 14.971 49.266 15.151 ;
     RECT  102.6 15.061 104.13 15.151 ;
     RECT  105.015 2.413 105.297 15.151 ;
     RECT  39.852 14.909 41.886 15.179 ;
     RECT  45.108 15.151 49.41 15.179 ;
     RECT  79.344 15.089 81.63 15.179 ;
     RECT  79.344 15.179 80.226 15.215 ;
     RECT  61.092 14.909 76.698 15.251 ;
     RECT  45.252 15.179 49.41 15.259 ;
     RECT  50.616 15.089 60.318 15.287 ;
     RECT  79.344 15.215 79.542 15.293 ;
     RECT  39.06 15.025 39.078 15.307 ;
     RECT  79.524 15.293 79.542 15.323 ;
     RECT  38.052 15.307 39.078 15.331 ;
     RECT  39.852 15.179 41.598 15.331 ;
     RECT  61.092 15.251 74.934 15.341 ;
     RECT  45.252 15.259 49.626 15.359 ;
     RECT  61.092 15.341 64.026 15.359 ;
     RECT  80.964 15.179 81.27 15.359 ;
     RECT  38.052 15.331 41.598 15.449 ;
     RECT  47.412 15.359 49.626 15.449 ;
     RECT  52.416 15.287 60.318 15.457 ;
     RECT  61.092 15.359 63.774 15.457 ;
     RECT  50.616 15.287 51.297 15.485 ;
     RECT  64.836 15.341 74.934 15.485 ;
     RECT  82.656 15.025 100.278 15.493 ;
     RECT  82.656 15.493 100.314 15.533 ;
     RECT  70.812 15.485 74.142 15.557 ;
     RECT  99.54 15.533 100.314 15.601 ;
     RECT  70.812 15.557 74.106 15.629 ;
     RECT  82.656 15.533 98.802 15.685 ;
     RECT  38.052 15.449 41.346 15.719 ;
     RECT  52.416 15.457 63.774 15.719 ;
     RECT  64.836 15.485 70.074 15.719 ;
     RECT  71.1 15.629 74.106 15.719 ;
     RECT  42.732 15.601 42.75 15.791 ;
     RECT  64.836 15.719 68.022 15.791 ;
     RECT  69.084 15.719 69.102 15.791 ;
     RECT  71.208 15.719 74.106 15.791 ;
     RECT  52.488 15.719 63.054 15.827 ;
     RECT  69.912 15.719 70.074 15.827 ;
     RECT  82.62 15.685 98.802 15.827 ;
     RECT  99.54 15.601 100.674 15.827 ;
     RECT  52.488 15.827 62.982 15.863 ;
     RECT  66.276 15.791 68.022 15.863 ;
     RECT  69.912 15.827 69.93 15.863 ;
     RECT  52.488 15.863 62.874 15.899 ;
     RECT  67.032 15.863 67.554 15.899 ;
     RECT  74.916 15.485 74.934 15.979 ;
     RECT  75.672 15.251 76.698 15.979 ;
     RECT  137.415 9.581 137.697 15.979 ;
     RECT  38.052 15.719 41.31 15.989 ;
     RECT  50.148 15.835 50.166 15.989 ;
     RECT  52.956 15.899 62.874 15.989 ;
     RECT  66.276 15.863 66.294 15.989 ;
     RECT  67.14 15.899 67.554 15.989 ;
     RECT  64.836 15.791 65.358 16.025 ;
     RECT  81.252 15.359 81.27 16.025 ;
     RECT  83.304 15.827 98.802 16.025 ;
     RECT  102.6 15.151 105.297 16.109 ;
     RECT  99.54 15.827 100.386 16.133 ;
     RECT  44.316 16.105 44.334 16.141 ;
     RECT  45.252 15.359 46.674 16.141 ;
     RECT  47.412 15.449 49.41 16.141 ;
     RECT  74.916 15.979 76.698 16.141 ;
     RECT  137.415 15.979 137.754 16.141 ;
     RECT  138.996 13.627 139.014 16.141 ;
     RECT  102.636 16.109 105.297 16.142 ;
     RECT  99.54 16.133 100.314 16.169 ;
     RECT  45.252 16.141 49.41 16.259 ;
     RECT  52.956 15.989 62.694 16.259 ;
     RECT  64.944 16.025 65.358 16.259 ;
     RECT  82.476 16.105 82.494 16.259 ;
     RECT  93.204 16.025 98.802 16.259 ;
     RECT  99.54 16.169 99.99 16.259 ;
     RECT  137.415 16.141 139.014 16.259 ;
     RECT  46.62 16.259 48.186 16.295 ;
     RECT  49.14 16.259 49.41 16.295 ;
     RECT  64.944 16.259 65.322 16.295 ;
     RECT  74.916 16.141 76.878 16.295 ;
     RECT  51.015 15.485 51.297 16.303 ;
     RECT  44.316 16.141 44.478 16.375 ;
     RECT  45.252 16.259 45.897 16.375 ;
     RECT  50.688 16.303 51.297 16.403 ;
     RECT  94.032 16.259 98.658 16.403 ;
     RECT  99.54 16.259 99.897 16.403 ;
     RECT  74.916 16.295 75.15 16.411 ;
     RECT  65.088 16.295 65.322 16.439 ;
     RECT  102.672 16.142 105.297 16.439 ;
     RECT  49.284 16.295 49.41 16.529 ;
     RECT  52.956 16.259 62.622 16.529 ;
     RECT  65.088 16.439 65.214 16.529 ;
     RECT  93.204 16.259 93.258 16.529 ;
     RECT  137.415 16.259 138.726 16.529 ;
     RECT  93.24 16.529 93.258 16.541 ;
     RECT  49.284 16.529 49.302 16.565 ;
     RECT  60.228 16.529 62.622 16.565 ;
     RECT  65.088 16.529 65.106 16.565 ;
     RECT  71.208 15.791 74.034 16.565 ;
     RECT  74.88 16.411 75.15 16.565 ;
     RECT  83.304 16.025 92.286 16.565 ;
     RECT  94.068 16.403 98.622 16.565 ;
     RECT  103.212 16.439 105.297 16.565 ;
     RECT  60.444 16.565 62.622 16.601 ;
     RECT  60.444 16.601 61.074 16.673 ;
     RECT  94.215 16.565 98.622 16.673 ;
     RECT  38.052 15.989 40.806 16.681 ;
     RECT  52.956 16.529 58.878 16.681 ;
     RECT  71.208 16.565 71.766 16.681 ;
     RECT  37.656 16.681 40.806 16.709 ;
     RECT  83.415 16.565 92.286 16.709 ;
     RECT  37.656 16.709 40.497 16.799 ;
     RECT  44.316 16.375 45.897 16.799 ;
     RECT  61.056 16.673 61.074 16.799 ;
     RECT  61.815 16.601 62.622 16.799 ;
     RECT  70.92 16.681 71.766 16.799 ;
     RECT  72.615 16.565 74.034 16.799 ;
     RECT  74.916 16.565 75.15 16.799 ;
     RECT  84.816 16.709 92.286 16.799 ;
     RECT  94.215 16.673 98.406 16.799 ;
     RECT  73.656 16.799 73.674 16.835 ;
     RECT  74.916 16.799 74.934 16.835 ;
     RECT  88.488 16.799 92.286 16.835 ;
     RECT  37.656 16.799 39.294 16.907 ;
     RECT  87.408 16.799 87.75 16.907 ;
     RECT  37.656 16.907 38.862 16.915 ;
     RECT  52.812 16.681 58.878 16.915 ;
     RECT  70.92 16.799 71.694 16.915 ;
     RECT  88.524 16.835 92.286 16.915 ;
     RECT  86.652 16.799 86.67 16.943 ;
     RECT  87.732 16.907 87.75 16.943 ;
     RECT  94.215 16.799 97.938 16.943 ;
     RECT  44.316 16.799 44.478 16.951 ;
     RECT  137.415 16.529 137.97 16.979 ;
     RECT  2.415 9.779 2.697 17.027 ;
     RECT  7.815 2.413 8.097 17.027 ;
     RECT  13.215 9.248 13.497 17.027 ;
     RECT  18.615 2.413 18.897 17.027 ;
     RECT  24.015 9.248 24.297 17.027 ;
     RECT  29.415 2.413 29.697 17.027 ;
     RECT  34.815 9.245 35.097 17.027 ;
     RECT  40.14 16.799 40.497 17.027 ;
     RECT  45.324 16.799 45.897 17.027 ;
     RECT  51.015 16.403 51.297 17.027 ;
     RECT  61.815 16.799 62.097 17.027 ;
     RECT  67.215 15.989 67.497 17.027 ;
     RECT  72.615 16.799 72.897 17.027 ;
     RECT  78.015 15.089 78.297 17.027 ;
     RECT  83.415 16.709 83.697 17.027 ;
     RECT  99.615 16.403 99.897 17.027 ;
     RECT  103.644 16.565 105.297 17.027 ;
     RECT  110.415 13.565 110.697 17.027 ;
     RECT  115.815 2.413 116.097 17.027 ;
     RECT  121.215 13.568 121.497 17.027 ;
     RECT  126.615 2.413 126.897 17.027 ;
     RECT  132.015 13.568 132.297 17.027 ;
     RECT  137.415 16.979 137.697 17.027 ;
     RECT  37.44 16.915 38.862 17.069 ;
     RECT  40.14 17.027 40.305 17.069 ;
     RECT  45.324 17.027 45.705 17.069 ;
     RECT  46.62 16.295 48.042 17.069 ;
     RECT  52.632 16.915 58.878 17.069 ;
     RECT  70.704 16.915 71.694 17.069 ;
     RECT  84.816 16.799 85.806 17.069 ;
     RECT  88.524 16.915 92.322 17.069 ;
     RECT  94.215 16.943 97.47 17.069 ;
     RECT  103.644 17.027 105.105 17.069 ;
     RECT  138.708 16.529 138.726 17.069 ;
     RECT  37.44 17.069 38.79 17.077 ;
     RECT  44.244 16.951 44.478 17.077 ;
     RECT  52.632 17.069 53.01 17.077 ;
     RECT  57.924 17.069 57.942 17.105 ;
     RECT  88.524 17.069 90.63 17.105 ;
     RECT  97.344 17.069 97.362 17.105 ;
     RECT  37.224 17.077 38.79 17.117 ;
     RECT  44.028 17.077 44.478 17.117 ;
     RECT  46.62 17.069 47.286 17.117 ;
     RECT  52.308 17.077 53.01 17.117 ;
     RECT  53.748 17.069 54.63 17.117 ;
     RECT  70.704 17.069 71.55 17.117 ;
     RECT  84.816 17.069 85.626 17.117 ;
     RECT  88.776 17.105 90.63 17.117 ;
     RECT  94.215 17.069 96.498 17.117 ;
     RECT  103.644 17.069 104.202 17.117 ;
     RECT  37.224 17.117 38.754 17.165 ;
     RECT  46.62 17.117 47.178 17.165 ;
     RECT  52.308 17.117 52.902 17.165 ;
     RECT  53.748 17.117 54.522 17.165 ;
     RECT  70.812 17.117 71.442 17.165 ;
     RECT  91.512 17.069 92.214 17.165 ;
     RECT  94.215 17.117 95.418 17.165 ;
     RECT  38.268 17.165 38.754 17.213 ;
     RECT  44.388 17.117 44.442 17.213 ;
     RECT  2.415 17.027 2.505 17.297 ;
     RECT  7.815 17.027 7.905 17.297 ;
     RECT  13.215 17.027 13.305 17.297 ;
     RECT  18.615 17.027 18.705 17.297 ;
     RECT  24.015 17.027 24.105 17.297 ;
     RECT  29.415 17.027 29.505 17.297 ;
     RECT  34.815 17.027 34.905 17.297 ;
     RECT  40.215 17.069 40.305 17.297 ;
     RECT  45.615 17.069 45.705 17.297 ;
     RECT  51.015 17.027 51.105 17.297 ;
     RECT  61.815 17.027 61.905 17.297 ;
     RECT  67.215 17.027 67.305 17.297 ;
     RECT  72.615 17.027 72.705 17.297 ;
     RECT  78.015 17.027 78.105 17.297 ;
     RECT  83.415 17.027 83.505 17.297 ;
     RECT  88.776 17.117 88.905 17.297 ;
     RECT  94.215 17.165 94.806 17.297 ;
     RECT  99.615 17.027 99.705 17.297 ;
     RECT  105.015 17.069 105.105 17.297 ;
     RECT  110.415 17.027 110.505 17.297 ;
     RECT  115.815 17.027 115.905 17.297 ;
     RECT  121.215 17.027 121.305 17.297 ;
     RECT  126.615 17.027 126.705 17.297 ;
     RECT  132.015 17.027 132.105 17.297 ;
     RECT  137.415 17.027 137.505 17.297 ;
     RECT  44.388 17.213 44.406 17.309 ;
     RECT  56.016 17.069 56.898 17.405 ;
     RECT  38.268 17.213 38.286 17.645 ;
     RECT  52.308 17.165 52.65 17.645 ;
     RECT  91.512 17.165 91.53 17.645 ;
     RECT  96.156 17.117 96.498 17.645 ;
     RECT  103.644 17.117 103.95 17.645 ;
     RECT  37.224 17.165 37.458 18.269 ;
     RECT  46.62 17.165 46.638 18.269 ;
     RECT  53.748 17.165 53.946 18.269 ;
     RECT  56.016 17.405 56.214 18.269 ;
     RECT  70.812 17.165 70.83 18.269 ;
     RECT  89.64 17.117 90.054 18.269 ;
     RECT  94.644 17.297 94.806 18.269 ;
     RECT  96.192 17.645 96.21 18.269 ;
     RECT  103.644 17.645 103.662 18.269 ;
     RECT  37.224 18.269 37.242 18.317 ;
     RECT  88.776 17.297 88.794 18.653 ;
     RECT  52.308 17.645 52.326 18.797 ;
     RECT  53.928 18.269 53.946 18.797 ;
     RECT  56.196 18.269 56.214 18.797 ;
     RECT  84.816 17.117 85.518 18.797 ;
     RECT  94.644 18.269 94.662 18.797 ;
     RECT  89.64 18.269 89.658 18.845 ;
     RECT  140.796 17.077 140.814 18.845 ;
     RECT  85.5 18.797 85.518 19.325 ;
    LAYER M4 ;
     RECT  0.06 8.64 0.137 9.096 ;
     RECT  0.137 8.784 0.517 9.096 ;
     RECT  0.517 8.784 0.569 9.288 ;
     RECT  0.569 8.928 2.408 9.288 ;
     RECT  2.408 2.148 2.512 17.292 ;
     RECT  2.512 2.418 2.704 17.022 ;
     RECT  4.165 9.648 4.309 9.672 ;
     RECT  4.309 9.648 4.453 9.864 ;
     RECT  4.453 8.976 4.597 9.864 ;
     RECT  4.597 8.784 5.569 9.864 ;
     RECT  5.569 8.736 7.808 9.864 ;
     RECT  7.808 2.148 7.912 17.292 ;
     RECT  7.912 2.148 8.104 17.022 ;
     RECT  8.629 1.728 8.849 1.752 ;
     RECT  9.277 5.088 9.349 5.112 ;
     RECT  9.349 5.088 9.395 5.832 ;
     RECT  9.395 5.808 10.469 5.832 ;
     RECT  8.104 8.736 13.208 9.864 ;
     RECT  13.208 2.148 13.312 17.292 ;
     RECT  13.312 2.418 13.504 17.022 ;
     RECT  13.504 8.736 18.608 9.864 ;
     RECT  18.608 2.148 18.712 17.292 ;
     RECT  18.712 2.418 18.904 17.022 ;
     RECT  18.904 8.736 24.008 9.864 ;
     RECT  24.008 2.148 24.112 17.292 ;
     RECT  24.112 2.418 24.304 17.022 ;
     RECT  24.304 8.736 29.408 9.864 ;
     RECT  29.408 2.148 29.512 17.292 ;
     RECT  29.512 2.418 29.704 17.022 ;
     RECT  29.704 8.736 34.808 9.864 ;
     RECT  34.808 2.148 34.912 17.292 ;
     RECT  34.912 2.418 35.104 17.022 ;
     RECT  37.213 18.288 37.429 18.312 ;
     RECT  37.429 18.24 37.715 18.312 ;
     RECT  37.753 17.088 37.765 17.112 ;
     RECT  37.715 18.24 37.907 18.264 ;
     RECT  37.765 17.088 38.257 17.16 ;
     RECT  38.257 17.088 38.341 17.64 ;
     RECT  38.041 15.312 38.761 15.336 ;
     RECT  38.341 17.088 38.765 17.208 ;
     RECT  38.761 15.312 38.801 15.432 ;
     RECT  38.765 17.088 38.801 17.112 ;
     RECT  35.104 8.736 40.208 9.864 ;
     RECT  38.801 15.408 40.208 15.432 ;
     RECT  40.208 2.148 40.312 17.292 ;
     RECT  40.312 2.418 40.504 17.022 ;
     RECT  42.757 13.632 42.841 13.656 ;
     RECT  44.017 17.088 44.149 17.112 ;
     RECT  40.504 14.64 44.305 15.48 ;
     RECT  44.149 17.088 44.305 17.304 ;
     RECT  44.305 14.64 44.417 17.304 ;
     RECT  44.417 14.64 44.445 17.208 ;
     RECT  44.445 14.88 44.453 17.208 ;
     RECT  44.453 14.88 44.524 17.112 ;
     RECT  40.504 8.736 45.608 9.864 ;
     RECT  44.524 14.88 45.608 16.296 ;
     RECT  45.608 2.148 45.712 17.292 ;
     RECT  45.712 2.418 45.904 17.022 ;
     RECT  45.904 14.496 46.541 15.48 ;
     RECT  46.541 14.976 46.829 15.48 ;
     RECT  46.609 18.24 46.979 18.264 ;
     RECT  46.933 17.088 47.125 17.112 ;
     RECT  47.125 17.088 47.222 17.16 ;
     RECT  47.222 17.088 47.308 17.112 ;
     RECT  46.829 15.024 47.333 15.48 ;
     RECT  47.333 15.264 49.237 15.48 ;
     RECT  45.904 8.736 51.008 9.864 ;
     RECT  49.237 14.448 51.008 15.48 ;
     RECT  51.008 2.148 51.112 17.292 ;
     RECT  51.112 2.418 51.304 17.022 ;
     RECT  51.304 14.448 52.693 15.48 ;
     RECT  52.621 17.616 52.705 17.64 ;
     RECT  52.297 18.768 52.787 18.792 ;
     RECT  52.837 17.136 52.933 17.16 ;
     RECT  52.933 17.088 52.934 17.16 ;
     RECT  52.934 17.088 53.021 17.112 ;
     RECT  53.737 18.24 53.917 18.264 ;
     RECT  53.917 18.24 54.323 18.792 ;
     RECT  54.323 18.768 54.419 18.792 ;
     RECT  54.469 17.136 54.565 17.16 ;
     RECT  54.565 17.088 54.566 17.16 ;
     RECT  54.061 13.056 54.637 13.08 ;
     RECT  52.693 14.448 54.637 15.528 ;
     RECT  54.566 17.088 54.652 17.112 ;
     RECT  54.637 13.056 55.033 15.528 ;
     RECT  55.033 12.864 55.433 15.528 ;
     RECT  54.097 11.808 55.681 11.832 ;
     RECT  55.433 12.864 55.681 15.48 ;
     RECT  56.005 18.24 56.077 18.264 ;
     RECT  56.077 17.616 56.185 18.264 ;
     RECT  51.304 8.736 56.408 9.864 ;
     RECT  55.681 11.808 56.408 15.48 ;
     RECT  56.185 17.616 56.408 18.792 ;
     RECT  56.408 2.148 56.512 18.792 ;
     RECT  56.512 2.418 56.531 18.792 ;
     RECT  56.531 18.768 56.627 18.792 ;
     RECT  56.531 2.418 56.704 17.4 ;
     RECT  56.704 17.376 56.909 17.4 ;
     RECT  56.704 12.768 57.377 15.816 ;
     RECT  57.377 13.056 57.74 15.816 ;
     RECT  56.704 11.664 57.805 11.688 ;
     RECT  57.74 13.056 57.953 16.776 ;
     RECT  57.805 11.664 57.973 11.976 ;
     RECT  57.973 11.328 58.06 11.976 ;
     RECT  58.06 11.472 58.489 11.976 ;
     RECT  57.953 13.056 58.489 15.816 ;
     RECT  58.489 11.472 59.701 15.816 ;
     RECT  59.701 11.472 59.797 16.584 ;
     RECT  59.797 11.376 60.005 16.584 ;
     RECT  60.005 11.376 60.257 14.808 ;
     RECT  60.257 13.104 60.323 14.808 ;
     RECT  60.257 11.376 60.433 11.976 ;
     RECT  60.433 10.848 60.545 11.976 ;
     RECT  60.545 10.944 61.765 11.976 ;
     RECT  60.323 13.104 61.765 14.76 ;
     RECT  56.704 8.736 61.808 9.864 ;
     RECT  61.765 10.944 61.808 14.76 ;
     RECT  60.005 15.792 61.808 16.584 ;
     RECT  61.808 2.148 61.912 17.292 ;
     RECT  61.912 2.418 62.104 17.022 ;
     RECT  62.104 8.736 62.675 16.776 ;
     RECT  62.675 8.736 63.173 15.336 ;
     RECT  63.173 10.848 63.569 15.336 ;
     RECT  63.173 8.736 64.429 9.864 ;
     RECT  63.569 11.424 64.753 15.336 ;
     RECT  64.429 8.736 64.825 10.008 ;
     RECT  64.753 10.992 64.825 15.336 ;
     RECT  64.825 8.736 64.829 15.336 ;
     RECT  64.829 8.736 65.729 13.128 ;
     RECT  65.729 8.736 65.797 10.008 ;
     RECT  65.797 8.448 65.837 10.008 ;
     RECT  65.729 10.992 66.017 13.128 ;
     RECT  66.017 11.376 66.085 13.128 ;
     RECT  64.829 14.208 66.085 15.336 ;
     RECT  65.837 8.448 66.229 9.864 ;
     RECT  66.085 11.376 66.445 15.336 ;
     RECT  66.445 11.376 66.805 15.576 ;
     RECT  66.229 8.208 67.208 9.864 ;
     RECT  66.805 11.376 67.208 15.816 ;
     RECT  67.208 2.148 67.312 17.292 ;
     RECT  67.312 2.418 67.504 17.022 ;
     RECT  67.504 12.288 67.601 15.816 ;
     RECT  67.601 12.288 67.673 15.576 ;
     RECT  67.673 12.288 69.037 14.952 ;
     RECT  69.037 11.952 69.061 14.952 ;
     RECT  69.061 11.952 69.148 15.768 ;
     RECT  69.144 5.04 69.205 5.064 ;
     RECT  67.504 8.208 69.251 9.864 ;
     RECT  69.205 5.04 69.932 5.592 ;
     RECT  69.148 11.952 70.009 14.952 ;
     RECT  69.932 4.512 70.019 5.592 ;
     RECT  70.009 11.424 70.153 14.952 ;
     RECT  69.251 8.736 70.229 9.864 ;
     RECT  70.22 1.104 70.307 1.128 ;
     RECT  70.117 2.304 70.549 2.328 ;
     RECT  70.019 4.896 70.697 5.592 ;
     RECT  70.693 0.528 70.777 0.552 ;
     RECT  70.837 0.096 71.057 0.168 ;
     RECT  70.153 11.424 71.197 15.096 ;
     RECT  70.549 1.728 71.221 2.328 ;
     RECT  71.197 11.424 71.233 16.008 ;
     RECT  70.801 18.24 71.315 18.264 ;
     RECT  70.693 17.088 71.365 17.112 ;
     RECT  71.233 11.184 71.377 16.008 ;
     RECT  71.221 1.728 71.413 2.952 ;
     RECT  70.697 4.896 71.461 5.544 ;
     RECT  71.365 17.088 71.462 17.16 ;
     RECT  71.462 17.088 71.561 17.112 ;
     RECT  71.413 1.152 71.633 2.952 ;
     RECT  71.057 0.096 71.669 0.12 ;
     RECT  70.229 8.736 71.693 9.576 ;
     RECT  71.377 10.704 71.693 16.008 ;
     RECT  71.461 4.656 71.701 5.544 ;
     RECT  71.701 3.984 72.205 5.544 ;
     RECT  71.633 1.728 72.209 2.952 ;
     RECT  72.209 2.148 72.608 2.952 ;
     RECT  72.205 3.984 72.608 5.592 ;
     RECT  71.693 8.736 72.608 16.008 ;
     RECT  72.608 2.148 72.712 17.292 ;
     RECT  72.712 2.304 72.904 17.022 ;
     RECT  72.904 2.304 73.469 5.736 ;
     RECT  73.469 2.832 73.564 5.736 ;
     RECT  73.564 2.832 73.577 4.68 ;
     RECT  73.577 2.832 73.721 4.488 ;
     RECT  73.721 2.928 73.937 4.488 ;
     RECT  73.937 2.928 74.081 2.952 ;
     RECT  73.937 4.128 74.189 4.488 ;
     RECT  72.904 10.704 74.329 12.312 ;
     RECT  74.189 4.464 74.405 4.488 ;
     RECT  73.564 5.664 74.405 5.736 ;
     RECT  74.405 5.664 74.581 5.688 ;
     RECT  74.329 10.656 74.801 12.312 ;
     RECT  74.801 10.704 74.905 12.312 ;
     RECT  72.904 13.392 74.905 16.008 ;
     RECT  72.904 8.736 74.917 9.576 ;
     RECT  74.581 5.184 74.981 5.688 ;
     RECT  74.905 10.704 75.269 16.008 ;
     RECT  74.917 8.544 77.605 9.576 ;
     RECT  75.269 10.704 77.605 15.288 ;
     RECT  74.981 5.184 78.008 5.208 ;
     RECT  77.605 8.544 78.008 15.288 ;
     RECT  78.008 2.148 78.112 17.292 ;
     RECT  78.112 2.418 78.304 17.022 ;
     RECT  78.304 8.688 78.905 15.288 ;
     RECT  78.905 8.688 79.049 12.312 ;
     RECT  79.049 10.56 79.121 12.312 ;
     RECT  79.121 10.608 79.265 12.312 ;
     RECT  78.905 13.44 79.373 15.288 ;
     RECT  79.265 10.704 79.805 12.312 ;
     RECT  79.805 10.992 79.873 12.312 ;
     RECT  79.373 13.44 79.873 14.952 ;
     RECT  79.049 8.688 80.989 9.576 ;
     RECT  79.873 10.992 81.241 14.952 ;
     RECT  81.212 15.984 81.241 16.008 ;
     RECT  81.241 10.992 81.299 16.008 ;
     RECT  81.299 10.992 82.465 15.72 ;
     RECT  80.989 8.688 82.753 9.72 ;
     RECT  82.465 10.896 82.753 15.72 ;
     RECT  78.304 5.184 83.408 5.208 ;
     RECT  82.753 8.688 83.408 15.72 ;
     RECT  83.408 2.148 83.512 17.292 ;
     RECT  83.512 2.418 83.704 17.022 ;
     RECT  83.704 10.896 83.981 15.48 ;
     RECT  83.981 10.992 84.131 15.48 ;
     RECT  84.131 13.536 84.697 15.48 ;
     RECT  84.697 13.536 85.036 16.44 ;
     RECT  84.131 10.992 85.165 12.312 ;
     RECT  84.805 18.768 85.331 18.792 ;
     RECT  85.237 17.616 85.427 17.64 ;
     RECT  85.445 19.296 85.529 19.32 ;
     RECT  85.036 16.272 85.573 16.44 ;
     RECT  85.573 16.272 85.66 17.112 ;
     RECT  85.165 10.992 85.777 12.552 ;
     RECT  85.777 10.656 85.849 12.552 ;
     RECT  85.849 10.56 85.955 12.552 ;
     RECT  85.955 10.56 86.645 12.312 ;
     RECT  86.645 10.656 86.717 12.312 ;
     RECT  85.036 13.536 87.037 15.24 ;
     RECT  85.66 16.272 87.037 16.296 ;
     RECT  86.717 10.944 87.073 12.312 ;
     RECT  87.073 10.944 88.261 12.552 ;
     RECT  88.261 10.848 88.333 12.552 ;
     RECT  87.037 13.536 88.513 16.296 ;
     RECT  83.704 8.688 88.808 9.576 ;
     RECT  88.333 10.704 88.808 12.552 ;
     RECT  88.513 13.536 88.808 16.92 ;
     RECT  88.808 2.148 88.912 17.292 ;
     RECT  88.912 2.418 89.104 17.112 ;
     RECT  88.765 18.624 89.612 18.648 ;
     RECT  89.612 18.624 89.699 18.84 ;
     RECT  89.104 8.688 90.241 9.576 ;
     RECT  89.104 10.704 90.241 17.112 ;
     RECT  90.241 8.688 90.323 17.112 ;
     RECT  90.025 18.24 90.515 18.264 ;
     RECT  90.323 17.088 90.641 17.112 ;
     RECT  90.323 8.688 91.525 16.104 ;
     RECT  91.501 17.616 91.667 17.64 ;
     RECT  91.525 8.688 91.763 16.584 ;
     RECT  91.763 10.992 91.813 16.584 ;
     RECT  91.813 10.992 91.829 17.16 ;
     RECT  91.829 10.992 92.045 15.528 ;
     RECT  92.045 10.992 92.189 14.808 ;
     RECT  91.829 16.512 92.225 17.16 ;
     RECT  92.189 10.992 92.621 13.56 ;
     RECT  92.621 10.992 92.837 11.736 ;
     RECT  92.225 16.512 93.229 16.536 ;
     RECT  93.229 16.272 93.805 16.536 ;
     RECT  93.805 16.08 94.057 16.536 ;
     RECT  91.763 8.688 94.208 9.576 ;
     RECT  92.837 10.992 94.208 11.496 ;
     RECT  92.621 12.768 94.208 13.56 ;
     RECT  92.189 14.64 94.208 14.808 ;
     RECT  94.057 15.792 94.208 16.536 ;
     RECT  94.208 2.148 94.312 17.292 ;
     RECT  94.312 2.418 94.504 17.022 ;
     RECT  94.504 15.792 94.673 17.022 ;
     RECT  94.633 18.768 94.777 18.792 ;
     RECT  94.777 18.24 95.219 18.792 ;
     RECT  94.504 11.472 95.357 14.808 ;
     RECT  95.357 11.712 95.681 14.808 ;
     RECT  94.673 15.792 96.041 16.104 ;
     RECT  95.365 17.088 96.145 17.16 ;
     RECT  95.219 18.24 96.145 18.264 ;
     RECT  96.041 15.984 96.361 16.104 ;
     RECT  96.145 17.088 96.361 18.264 ;
     RECT  96.361 15.984 96.401 18.264 ;
     RECT  96.401 16.56 96.419 18.264 ;
     RECT  95.681 11.712 96.541 14.76 ;
     RECT  96.419 16.56 96.611 17.64 ;
     RECT  96.541 11.472 96.853 14.76 ;
     RECT  96.611 16.56 96.899 16.632 ;
     RECT  96.853 11.472 97.013 14.808 ;
     RECT  96.899 16.56 97.157 16.584 ;
     RECT  97.013 12 97.225 14.808 ;
     RECT  97.225 12 98.053 15.096 ;
     RECT  98.053 12 98.125 15.672 ;
     RECT  98.125 12 98.149 16.008 ;
     RECT  98.149 11.04 98.161 16.008 ;
     RECT  98.161 11.04 98.209 16.104 ;
     RECT  98.209 11.04 98.525 15.096 ;
     RECT  98.525 11.04 98.605 13.656 ;
     RECT  98.209 16.08 98.629 16.104 ;
     RECT  98.525 15.072 99.385 15.096 ;
     RECT  98.629 16.08 99.385 16.392 ;
     RECT  94.504 8.688 99.608 9.576 ;
     RECT  98.605 11.04 99.608 11.256 ;
     RECT  98.605 12.72 99.608 13.656 ;
     RECT  99.385 15.072 99.608 16.392 ;
     RECT  99.608 2.148 99.712 17.292 ;
     RECT  99.712 2.418 99.904 17.022 ;
     RECT  99.904 11.232 100.979 11.256 ;
     RECT  99.904 15.504 102.849 16.104 ;
     RECT  102.849 15.504 102.947 16.152 ;
     RECT  102.947 15.984 103.861 16.152 ;
     RECT  103.861 15.984 103.921 17.112 ;
     RECT  103.633 18.24 103.921 18.264 ;
     RECT  103.921 15.984 103.993 18.264 ;
     RECT  103.993 15.936 104.005 18.264 ;
     RECT  104.005 15.936 104.033 17.112 ;
     RECT  104.005 18.24 104.099 18.264 ;
     RECT  99.904 8.688 105.008 9.576 ;
     RECT  99.904 13.536 105.008 13.56 ;
     RECT  104.033 15.936 105.008 16.008 ;
     RECT  104.033 17.088 105.008 17.112 ;
     RECT  105.008 2.148 105.112 17.292 ;
     RECT  105.112 2.418 105.304 17.022 ;
     RECT  105.304 8.688 110.408 9.576 ;
     RECT  105.304 13.536 110.408 13.56 ;
     RECT  105.304 15.984 110.408 16.008 ;
     RECT  110.408 2.148 110.512 17.292 ;
     RECT  110.512 2.418 110.704 17.022 ;
     RECT  110.704 8.688 115.808 9.576 ;
     RECT  110.704 13.536 115.808 13.56 ;
     RECT  110.704 15.984 115.808 16.008 ;
     RECT  115.808 2.148 115.912 17.292 ;
     RECT  115.912 2.418 116.104 17.022 ;
     RECT  116.104 8.688 121.208 9.576 ;
     RECT  116.104 13.536 121.208 13.56 ;
     RECT  116.104 15.984 121.208 16.008 ;
     RECT  121.208 2.148 121.312 17.292 ;
     RECT  121.312 2.418 121.504 17.022 ;
     RECT  121.504 8.688 126.608 9.576 ;
     RECT  121.504 13.536 126.608 13.56 ;
     RECT  121.504 15.984 126.608 16.008 ;
     RECT  126.608 2.148 126.712 17.292 ;
     RECT  126.712 2.418 126.904 17.022 ;
     RECT  126.904 8.688 132.008 9.576 ;
     RECT  126.904 13.536 132.008 13.56 ;
     RECT  126.904 15.984 132.008 16.008 ;
     RECT  132.008 2.148 132.112 17.292 ;
     RECT  132.112 2.418 132.304 17.022 ;
     RECT  132.304 13.536 134.521 13.56 ;
     RECT  134.521 13.536 134.561 13.656 ;
     RECT  132.304 8.688 137.408 9.576 ;
     RECT  134.561 13.632 137.408 13.656 ;
     RECT  132.304 15.984 137.408 16.008 ;
     RECT  137.408 2.148 137.512 17.292 ;
     RECT  137.512 2.418 137.704 17.022 ;
     RECT  137.704 15.984 137.765 16.008 ;
     RECT  137.704 13.632 139.025 13.656 ;
     RECT  137.704 8.688 139.241 9.576 ;
     RECT  139.241 8.688 139.777 9.096 ;
     RECT  140.785 18.816 141.155 18.84 ;
     RECT  139.777 8.64 142.524 9.096 ;
    LAYER M5 ;
     RECT  8.64 0.016 8.664 1.763 ;
     RECT  70.128 0.016 72.456 2.137 ;
     RECT  2.4 2.137 2.52 2.151 ;
     RECT  13.2 2.137 13.32 2.151 ;
     RECT  18.6 2.137 18.72 2.151 ;
     RECT  24 2.137 24.12 2.151 ;
     RECT  29.4 2.137 29.52 2.151 ;
     RECT  34.8 2.137 34.92 2.151 ;
     RECT  40.2 2.137 40.32 2.151 ;
     RECT  45.6 2.137 45.72 2.151 ;
     RECT  51 2.137 51.12 2.151 ;
     RECT  56.4 2.137 56.52 2.151 ;
     RECT  61.8 2.137 61.92 2.151 ;
     RECT  67.2 2.137 67.32 2.151 ;
     RECT  70.128 2.137 72.72 2.151 ;
     RECT  78 2.137 78.12 2.151 ;
     RECT  83.4 2.137 83.52 2.151 ;
     RECT  88.8 2.137 88.92 2.151 ;
     RECT  94.2 2.137 94.32 2.151 ;
     RECT  99.6 2.137 99.72 2.151 ;
     RECT  105 2.137 105.12 2.151 ;
     RECT  110.4 2.137 110.52 2.151 ;
     RECT  115.8 2.137 115.92 2.151 ;
     RECT  121.2 2.137 121.32 2.151 ;
     RECT  126.6 2.137 126.72 2.151 ;
     RECT  132 2.137 132.12 2.151 ;
     RECT  137.4 2.137 137.52 2.151 ;
     RECT  70.128 2.151 72.912 2.339 ;
     RECT  71.232 2.339 72.912 2.963 ;
     RECT  71.472 2.963 72.912 4.691 ;
     RECT  72.288 4.691 72.912 4.739 ;
     RECT  72.6 4.739 72.912 4.837 ;
     RECT  69.984 4.501 70.008 4.931 ;
     RECT  83.4 2.151 83.712 5.173 ;
     RECT  72.6 4.837 73.512 5.747 ;
     RECT  67.2 2.151 67.512 8.197 ;
     RECT  69.216 5.029 69.24 8.243 ;
     RECT  74.928 5.653 74.952 8.579 ;
     RECT  66.24 8.197 67.512 8.723 ;
     RECT  40.2 2.151 40.512 9.013 ;
     RECT  9.36 5.077 9.384 9.251 ;
     RECT  0.528 9.061 0.552 9.299 ;
     RECT  4.32 0.016 4.344 9.875 ;
     RECT  72.6 5.747 72.912 9.877 ;
     RECT  98.16 11.029 98.184 11.221 ;
     RECT  100.944 9.493 100.968 11.267 ;
     RECT  61.8 2.151 62.112 11.413 ;
     RECT  91.728 10.501 91.752 11.507 ;
     RECT  82.512 5.173 83.712 11.749 ;
     RECT  71.712 9.877 72.912 11.845 ;
     RECT  57.984 11.317 58.008 11.891 ;
     RECT  71.28 11.845 72.912 11.891 ;
     RECT  98.16 11.221 98.568 12.035 ;
     RECT  61.8 11.413 62.28 12.083 ;
     RECT  64.704 11.413 64.728 12.179 ;
     RECT  88.8 2.151 89.112 12.373 ;
     RECT  87.984 12.373 89.112 12.517 ;
     RECT  85.92 11.221 85.944 12.563 ;
     RECT  82.512 11.749 84.12 12.611 ;
     RECT  94.2 2.151 94.512 12.757 ;
     RECT  71.28 11.891 71.304 13.139 ;
     RECT  95.712 12.757 95.736 13.139 ;
     RECT  93.504 12.757 94.512 13.283 ;
     RECT  67.2 8.723 67.512 13.573 ;
     RECT  58.8 12.997 58.824 13.715 ;
     RECT  87.984 12.517 89.496 13.715 ;
     RECT  94.2 13.283 94.512 14.197 ;
     RECT  98.16 12.035 98.184 14.197 ;
     RECT  66.816 13.573 67.512 14.243 ;
     RECT  87.984 13.715 89.112 14.291 ;
     RECT  73.92 13.381 73.944 14.387 ;
     RECT  91.728 12.901 91.752 14.387 ;
     RECT  82.512 12.611 83.712 14.389 ;
     RECT  82.176 14.389 83.712 14.435 ;
     RECT  45.6 2.151 45.912 14.485 ;
     RECT  59.808 11.365 59.832 14.485 ;
     RECT  42.768 13.621 42.792 14.675 ;
     RECT  88.32 14.291 89.112 14.675 ;
     RECT  75.648 13.861 75.672 14.723 ;
     RECT  59.712 14.485 59.832 14.773 ;
     RECT  96.576 14.725 96.6 14.773 ;
     RECT  94.2 14.197 95.4 14.819 ;
     RECT  44.352 14.629 44.376 14.915 ;
     RECT  82.176 14.435 82.2 14.917 ;
     RECT  98.064 14.197 98.184 15.061 ;
     RECT  99.6 2.151 99.912 15.061 ;
     RECT  85.008 14.533 85.032 15.203 ;
     RECT  52.32 14.725 52.344 15.299 ;
     RECT  61.8 12.083 62.112 15.301 ;
     RECT  45.6 14.485 46.344 15.347 ;
     RECT  81.264 14.917 82.2 15.443 ;
     RECT  40.2 9.013 40.92 15.491 ;
     RECT  90.768 14.725 91.56 15.493 ;
     RECT  98.064 15.061 99.912 15.683 ;
     RECT  69.072 14.917 69.096 15.779 ;
     RECT  59.712 14.773 60.312 15.827 ;
     RECT  81.264 15.443 81.288 16.019 ;
     RECT  84.96 15.445 84.984 16.019 ;
     RECT  90.768 15.493 91.752 16.019 ;
     RECT  98.16 15.683 99.912 16.019 ;
     RECT  102.912 15.493 102.936 16.163 ;
     RECT  98.64 16.019 99.912 16.403 ;
     RECT  59.712 15.827 59.736 16.595 ;
     RECT  91.536 16.019 91.752 16.595 ;
     RECT  96.576 14.773 96.888 16.643 ;
     RECT  57.792 15.781 57.816 16.787 ;
     RECT  61.8 15.301 62.664 16.787 ;
     RECT  88.8 14.675 89.112 16.885 ;
     RECT  90.288 16.501 90.312 16.885 ;
     RECT  88.8 16.885 90.312 17.077 ;
     RECT  91.728 16.595 91.752 17.077 ;
     RECT  94.2 14.819 94.512 17.077 ;
     RECT  96.576 16.643 96.6 17.077 ;
     RECT  105 2.151 105.312 17.077 ;
     RECT  37.968 17.077 38.616 17.125 ;
     RECT  52.944 17.077 52.968 17.125 ;
     RECT  54.576 17.077 54.6 17.125 ;
     RECT  44.256 17.077 44.472 17.269 ;
     RECT  2.4 2.151 2.712 17.289 ;
     RECT  7.8 2.137 8.112 17.289 ;
     RECT  13.2 2.151 13.512 17.289 ;
     RECT  18.6 2.151 18.912 17.289 ;
     RECT  24 2.151 24.312 17.289 ;
     RECT  29.4 2.151 29.712 17.289 ;
     RECT  34.8 2.151 35.112 17.289 ;
     RECT  40.2 15.491 40.512 17.289 ;
     RECT  45.6 15.347 45.912 17.289 ;
     RECT  51 2.151 51.312 17.289 ;
     RECT  61.8 16.787 62.112 17.289 ;
     RECT  67.2 14.243 67.512 17.289 ;
     RECT  72.6 11.891 72.912 17.289 ;
     RECT  78 2.151 78.312 17.289 ;
     RECT  83.4 14.435 83.712 17.289 ;
     RECT  99.6 16.403 99.912 17.289 ;
     RECT  103.872 17.077 105.312 17.289 ;
     RECT  110.4 2.151 110.712 17.289 ;
     RECT  115.8 2.151 116.112 17.289 ;
     RECT  121.2 2.151 121.512 17.289 ;
     RECT  126.6 2.151 126.912 17.289 ;
     RECT  132 2.151 132.312 17.289 ;
     RECT  137.4 2.151 137.712 17.289 ;
     RECT  2.4 17.289 2.52 17.303 ;
     RECT  7.8 17.289 7.92 17.303 ;
     RECT  13.2 17.289 13.32 17.303 ;
     RECT  18.6 17.289 18.72 17.303 ;
     RECT  24 17.289 24.12 17.303 ;
     RECT  29.4 17.289 29.52 17.303 ;
     RECT  34.8 17.289 34.92 17.303 ;
     RECT  40.2 17.289 40.32 17.303 ;
     RECT  45.6 17.289 45.72 17.303 ;
     RECT  51 17.289 51.12 17.303 ;
     RECT  61.8 17.289 61.92 17.303 ;
     RECT  67.2 17.289 67.32 17.303 ;
     RECT  72.6 17.289 72.72 17.303 ;
     RECT  78 17.289 78.12 17.303 ;
     RECT  83.4 17.289 83.52 17.303 ;
     RECT  88.8 17.077 90.6 17.303 ;
     RECT  94.2 17.077 95.496 17.303 ;
     RECT  99.6 17.289 99.72 17.303 ;
     RECT  103.872 17.289 105.12 17.303 ;
     RECT  110.4 17.289 110.52 17.303 ;
     RECT  115.8 17.289 115.92 17.303 ;
     RECT  121.2 17.289 121.32 17.303 ;
     RECT  126.6 17.289 126.72 17.303 ;
     RECT  132 17.289 132.12 17.303 ;
     RECT  137.4 17.289 137.52 17.303 ;
     RECT  52.848 17.125 52.968 17.605 ;
     RECT  85.584 17.077 85.608 17.605 ;
     RECT  91.728 17.077 91.944 17.605 ;
     RECT  95.28 17.303 95.496 17.605 ;
     RECT  96.48 17.077 96.6 17.605 ;
     RECT  47.04 17.077 47.256 18.229 ;
     RECT  54.48 17.125 54.6 18.229 ;
     RECT  37.776 17.125 38.616 18.277 ;
     RECT  89.568 17.303 90.6 18.613 ;
     RECT  85.392 17.605 85.608 18.757 ;
     RECT  95.28 17.605 96.6 18.757 ;
     RECT  37.68 18.277 38.616 19.408 ;
     RECT  44.16 17.269 44.472 19.408 ;
     RECT  46.944 18.229 47.256 19.408 ;
     RECT  52.656 17.605 52.968 19.408 ;
     RECT  54.288 18.229 54.6 19.408 ;
     RECT  56.4 2.151 56.712 19.408 ;
     RECT  71.184 17.077 71.496 19.408 ;
     RECT  85.296 18.757 85.608 19.408 ;
     RECT  89.472 18.613 90.6 19.408 ;
     RECT  91.632 17.605 91.944 19.408 ;
     RECT  95.184 18.757 96.6 19.408 ;
     RECT  103.872 17.303 104.184 19.408 ;
     RECT  141.12 18.805 141.144 19.408 ;
  END
END ot_s81_pq_rwbc15
END LIBRARY
